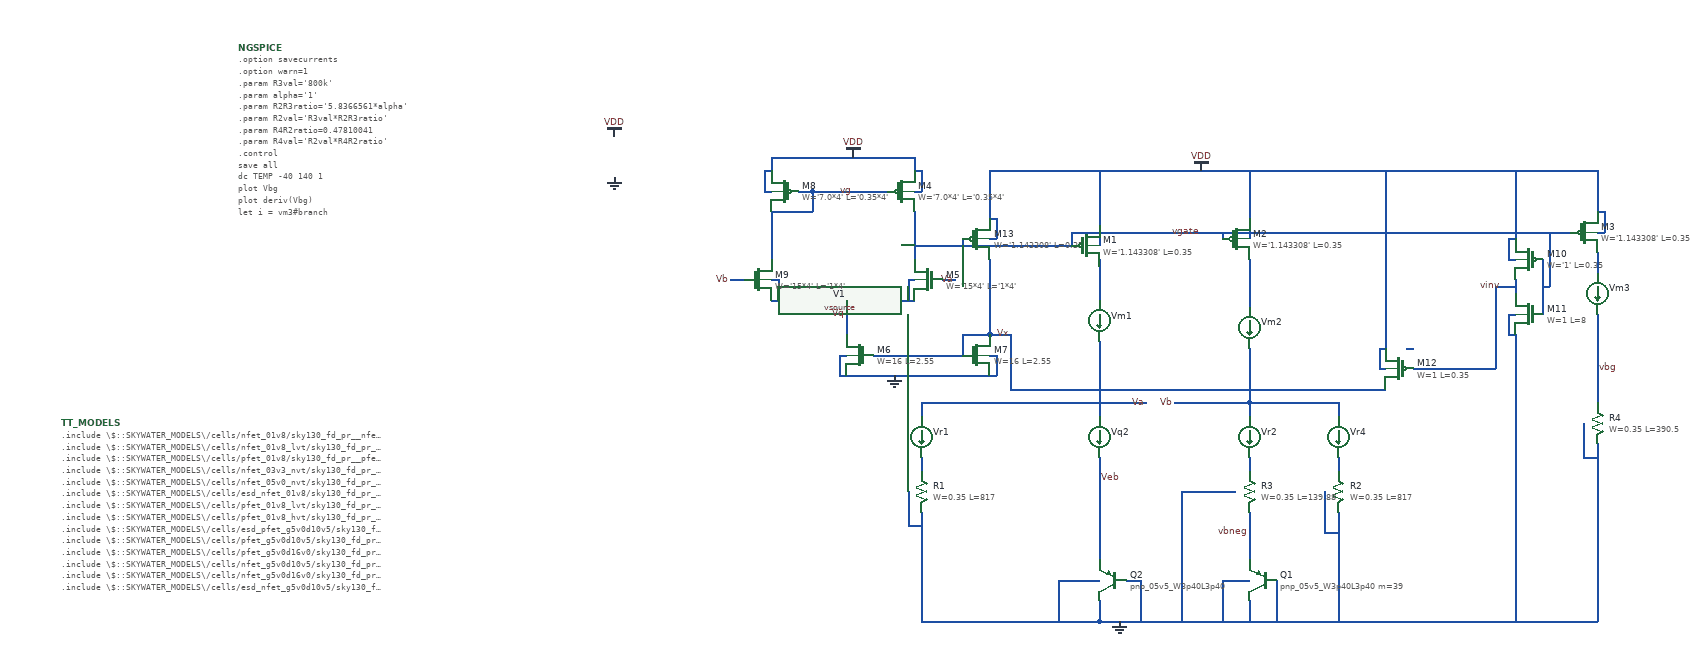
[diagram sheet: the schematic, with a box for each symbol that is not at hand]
v {xschem version=2.9.9 file_version=1.2 }
G {}
K {}
V {}
S {}
E {}
N 510 -220 760 -220 { lab=Va}
N 890 -220 990 -220 { lab=Vb}
N 990 -220 1120 -220 { lab=Vb}
N 770 70 770 100 { lab=GND}
N 770 100 870 100 { lab=GND}
N 580 100 770 100 { lab=GND}
N 710 40 770 40 { lab=GND}
N 710 40 710 100 { lab=GND}
N 830 -220 840 -220 { lab=Va}
N 700 -560 920 -560 { lab=VDD}
N 920 -560 1180 -560 { lab=VDD}
N 990 -220 990 -200 { lab=Vb}
N 990 -300 990 -220 { lab=Vb}
N 1500 -350 1500 -320 { lab=vbg}
N 1500 -320 1500 -220 { lab=vbg}
N 990 -140 990 -120 { lab=#net1}
N 1120 -220 1120 -200 { lab=Vb}
N 1120 -140 1120 -120 { lab=#net2}
N 510 -220 510 -200 { lab=Va}
N 510 -140 510 -120 { lab=#net3}
N 990 -430 990 -360 { lab=#net4}
N 990 -60 990 -40 { lab=vbneg}
N 990 -40 990 0 { lab=vbneg}
N 990 0 990 10 { lab=vbneg}
N 870 100 990 100 { lab=GND}
N 510 -60 510 100 { lab=GND}
N 1120 -60 1120 100 { lab=GND}
N 1500 -160 1500 100 { lab=GND}
N 920 100 1180 100 { lab=GND}
N 1030 40 1030 100 { lab=GND}
N 770 -220 770 -200 { lab=Va}
N 990 70 990 100 { lab=GND}
N 950 40 990 40 { lab=GND}
N 950 40 950 100 { lab=GND}
N 810 40 830 40 { lab=GND}
N 830 40 830 100 { lab=GND}
N 490 -90 490 -40 { lab=GND}
N 490 -40 510 -40 { lab=GND}
N 1100 -90 1100 -30 { lab=GND}
N 1100 -30 1120 -30 { lab=GND}
N 890 -90 970 -90 { lab=GND}
N 890 -90 890 100 { lab=GND}
N 1480 -190 1480 -140 { lab=GND}
N 1480 -140 1500 -140 { lab=GND}
N 770 -140 770 10 { lab=Veb}
N 990 -500 990 -490 { lab=VDD}
N 1500 -420 1500 -410 { lab=#net5}
N 770 -310 770 -210 { lab=Va}
N 880 -220 890 -220 { lab=Vb}
N 770 -430 770 -370 { lab=#net6}
N 990 -490 990 -460 { lab=VDD}
N 730 -470 730 -460 { lab=vgate}
N 770 -490 770 -460 { lab=VDD}
N 290 -500 350 -500 { lab=vg}
N 350 -530 350 -500 { lab=vg}
N 330 -530 350 -530 { lab=vg}
N 350 -530 460 -530 { lab=vg}
N 290 -580 290 -560 { lab=VDD}
N 290 -580 500 -580 { lab=VDD}
N 500 -580 500 -560 { lab=VDD}
N 290 -500 290 -430 { lab=vg}
N 500 -500 500 -430 { lab=vgate}
N 540 -400 560 -400 { lab=Va}
N 230 -400 250 -400 { lab=Vb}
N 290 -370 500 -370 { lab=Vq}
N 500 -530 510 -530 { lab=VDD}
N 510 -560 510 -530 { lab=VDD}
N 500 -560 510 -560 { lab=VDD}
N 280 -530 290 -530 { lab=VDD}
N 280 -560 280 -530 { lab=VDD}
N 280 -560 290 -560 { lab=VDD}
N 290 -400 300 -400 { lab=Vq}
N 300 -400 300 -370 { lab=Vq}
N 490 -400 500 -400 { lab=Vq}
N 490 -400 490 -370 { lab=Vq}
N 390 -290 400 -290 { lab=GND}
N 390 -290 390 -260 { lab=GND}
N 390 -260 400 -260 { lab=GND}
N 400 -370 400 -320 { lab=Vq}
N 440 -290 570 -290 { lab=Vx}
N 610 -290 620 -290 { lab=GND}
N 610 -430 610 -320 { lab=Vx}
N 610 -560 660 -560 { lab=VDD}
N 470 -260 610 -260 { lab=GND}
N 400 -260 470 -260 { lab=GND}
N 570 -320 570 -290 { lab=Vx}
N 570 -320 610 -320 { lab=Vx}
N 610 -560 610 -490 { lab=VDD}
N 660 -560 700 -560 { lab=VDD}
N 730 -460 730 -450 { lab=vgate}
N 500 -450 660 -450 { lab=vgate}
N 620 -290 620 -260 { lab=GND}
N 610 -260 620 -260 { lab=GND}
N 570 -460 570 -450 { lab=vgate}
N 610 -460 620 -460 { lab=VDD}
N 620 -490 620 -460 { lab=VDD}
N 610 -490 620 -490 { lab=VDD}
N 1380 -560 1380 -460 { lab=VDD}
N 1420 -430 1420 -350 { lab=vgate}
N 1370 -430 1380 -430 { lab=VDD}
N 1370 -460 1370 -430 { lab=VDD}
N 1370 -460 1380 -460 { lab=VDD}
N 1380 -400 1380 -380 { lab=vinv}
N 1370 -350 1380 -350 { lab=GND}
N 1370 -350 1370 -320 { lab=GND}
N 1370 -320 1380 -320 { lab=GND}
N 1380 -320 1380 100 { lab=GND}
N 1420 -390 1430 -390 { lab=vgate}
N 1430 -470 1430 -390 { lab=vgate}
N 1190 -560 1190 -300 { lab=VDD}
N 1180 -270 1190 -270 { lab=VDD}
N 1180 -300 1180 -270 { lab=VDD}
N 1220 -300 1230 -300 { lab=#net7}
N 1350 -390 1350 -270 { lab=vinv}
N 1350 -390 1380 -390 { lab=vinv}
N 1180 -560 1470 -560 { lab=VDD}
N 1180 100 1470 100 { lab=GND}
N 640 -240 1190 -240 { lab=Vx}
N 640 -320 640 -240 { lab=Vx}
N 610 -320 640 -320 { lab=Vx}
N 1170 -470 1460 -470 { lab=vgate}
N 760 -220 830 -220 { lab=Va}
N 510 100 580 100 { lab=GND}
N 770 -560 770 -490 { lab=VDD}
N 990 -560 990 -500 { lab=VDD}
N 660 -450 730 -450 { lab=vgate}
N 730 -470 920 -470 { lab=vgate}
N 920 -470 1170 -470 { lab=vgate}
N 950 -470 950 -460 { lab=vgate}
N 1180 -300 1190 -300 { lab=VDD}
N 1470 -560 1500 -560 { lab=VDD}
N 1230 -270 1350 -270 { lab=vinv}
N 1470 100 1500 100 { lab=GND}
N 1500 -440 1500 -420 { lab=#net5}
N 1500 -470 1510 -470 { lab=VDD}
N 1510 -500 1510 -470 { lab=VDD}
N 1500 -500 1510 -500 { lab=VDD}
N 1500 -560 1500 -500 { lab=VDD}
N 770 -460 770 -450 { lab=VDD}
C {devices/code.sym} -750 -190 0 0 {name=TT_MODELS
only_toplevel=true
format="tcleval( @value )"
value="
.include \\\\$::SKYWATER_MODELS\\\\/cells/nfet_01v8/sky130_fd_pr__nfet_01v8__tt.corner.spice
.include \\\\$::SKYWATER_MODELS\\\\/cells/nfet_01v8_lvt/sky130_fd_pr__nfet_01v8_lvt__tt.corner.spice
.include \\\\$::SKYWATER_MODELS\\\\/cells/pfet_01v8/sky130_fd_pr__pfet_01v8__tt.corner.spice
.include \\\\$::SKYWATER_MODELS\\\\/cells/nfet_03v3_nvt/sky130_fd_pr__nfet_03v3_nvt__tt.corner.spice
.include \\\\$::SKYWATER_MODELS\\\\/cells/nfet_05v0_nvt/sky130_fd_pr__nfet_05v0_nvt__tt.corner.spice
.include \\\\$::SKYWATER_MODELS\\\\/cells/esd_nfet_01v8/sky130_fd_pr__esd_nfet_01v8__tt.corner.spice
.include \\\\$::SKYWATER_MODELS\\\\/cells/pfet_01v8_lvt/sky130_fd_pr__pfet_01v8_lvt__tt.corner.spice
.include \\\\$::SKYWATER_MODELS\\\\/cells/pfet_01v8_hvt/sky130_fd_pr__pfet_01v8_hvt__tt.corner.spice
.include \\\\$::SKYWATER_MODELS\\\\/cells/esd_pfet_g5v0d10v5/sky130_fd_pr__esd_pfet_g5v0d10v5__tt.corner.spice
.include \\\\$::SKYWATER_MODELS\\\\/cells/pfet_g5v0d10v5/sky130_fd_pr__pfet_g5v0d10v5__tt.corner.spice
.include \\\\$::SKYWATER_MODELS\\\\/cells/pfet_g5v0d16v0/sky130_fd_pr__pfet_g5v0d16v0__tt.corner.spice
.include \\\\$::SKYWATER_MODELS\\\\/cells/nfet_g5v0d10v5/sky130_fd_pr__nfet_g5v0d10v5__tt.corner.spice
.include \\\\$::SKYWATER_MODELS\\\\/cells/nfet_g5v0d16v0/sky130_fd_pr__nfet_g5v0d16v0__tt_discrete.corner.spice
.include \\\\$::SKYWATER_MODELS\\\\/cells/esd_nfet_g5v0d10v5/sky130_fd_pr__esd_nfet_g5v0d10v5__tt.corner.spice
.include \\\\$::SKYWATER_MODELS\\\\/models/corners/tt/nonfet.spice
* Mismatch parameters
.include \\\\$::SKYWATER_MODELS\\\\/cells/nfet_01v8/sky130_fd_pr__nfet_01v8__mismatch.corner.spice
.include \\\\$::SKYWATER_MODELS\\\\/cells/pfet_01v8/sky130_fd_pr__pfet_01v8__mismatch.corner.spice
.include \\\\$::SKYWATER_MODELS\\\\/cells/nfet_01v8_lvt/sky130_fd_pr__nfet_01v8_lvt__mismatch.corner.spice
.include \\\\$::SKYWATER_MODELS\\\\/cells/pfet_01v8_lvt/sky130_fd_pr__pfet_01v8_lvt__mismatch.corner.spice
.include \\\\$::SKYWATER_MODELS\\\\/cells/pfet_01v8_hvt/sky130_fd_pr__pfet_01v8_hvt__mismatch.corner.spice
.include \\\\$::SKYWATER_MODELS\\\\/cells/nfet_g5v0d10v5/sky130_fd_pr__nfet_g5v0d10v5__mismatch.corner.spice
.include \\\\$::SKYWATER_MODELS\\\\/cells/pfet_g5v0d10v5/sky130_fd_pr__pfet_g5v0d10v5__mismatch.corner.spice
.include \\\\$::SKYWATER_MODELS\\\\/cells/nfet_05v0_nvt/sky130_fd_pr__nfet_05v0_nvt__mismatch.corner.spice
.include \\\\$::SKYWATER_MODELS\\\\/cells/nfet_03v3_nvt/sky130_fd_pr__nfet_03v3_nvt__mismatch.corner.spice
* Resistor\\\\$::SKYWATER_MODELS\\\\/Capacitor
.include \\\\$::SKYWATER_MODELS\\\\/models/r+c/res_typical__cap_typical.spice
.include \\\\$::SKYWATER_MODELS\\\\/models/r+c/res_typical__cap_typical__lin.spice
* Special cells
.include \\\\$::SKYWATER_MODELS\\\\/models/corners/tt/specialized_cells.spice
* All models
.include \\\\$::SKYWATER_MODELS\\\\/models/all.spice
.include \\\\$::SKYWATER_MODELS\\\\/cells/pnp_05v5/sky130_fd_pr__pnp_05v5_W3p40L3p40.model.spice
* Corner
.include \\\\$::SKYWATER_MODELS\\\\/models/corners/tt/rf.spice
"}
C {devices/vsource.sym} 60 -580 0 0 {name=V1 net_name=true value=1.8}
C {devices/vdd.sym} 60 -610 0 0 {name=l8 lab=VDD}
C {devices/gnd.sym} 60 -550 0 0 {name=l9 lab=GND}
C {devices/code_shown.sym} -490 -740 0 0 {name=NGSPICE
only_toplevel=true
spice_ignore=false
value="
.option savecurrents
.option warn=1
.param R3val='800k'
.param alpha='1'
.param R2R3ratio='5.8366561*alpha'
.param R2val='R3val*R2R3ratio' 
.param R4R2ratio=0.47810041
.param R4val='R2val*R4R2ratio'
.control
save all
dc TEMP -40 140 1
plot Vbg
plot deriv(Vbg)
let i = vm3#branch
let indx = 67
*indx is the index of temperature sweep for 27degC
echo 'Vbg @ 27degC'
let vbg27c = vbg[indx]
print vbg27c
echo 'dVbe/degC & ppm @ 27degC'
print deriv(vbg)[indx] deriv(vbg)[indx]/vbg27c
echo 'ppm real'
print (vbg[110]-vbg[40])/vbg[67]/(70-0)*1e6
plot deriv(vbg)/vbg27c
plot v(va, vb) vs i
plot vm1#branch vm2#branch vm3#branch
let vsg = vdd - vgate
let vsd1 = vdd - va
let vsd2 = vdd - vb
let vsd3 = vdd - vbg
let vthp = @m.xm1.msky130_fd_pr__pfet_01v8_lvt['vth']
let vov = vsg - vthp
plot vov vsd1 vsd2 vsd3
let deltav = vb - vbneg
let r4 =vbg/vm3#branch
let r1 =va/vr1#branch
let r2 =vb/vr4#branch
let r3 =deltav/vr2#branch
let vptat =(r2/r3*deltav)
let sum = veb+vptat
plot veb vptat sum
plot deriv(veb) deriv(vptat)
let TCratio=deriv(veb)/deriv(vptat)
plot TCratio
plot vb - va
echo 'alpha correction factor'
let alpha=TCratio[indx]
print alpha
let gm1=@m.xm1.msky130_fd_pr__pfet_01v8_lvt[gm]
let gm2=@m.xm2.msky130_fd_pr__pfet_01v8_lvt[gm]
let Av2=gm2 * ((r3 + r3/ln(39)) * r2 / (r3 + r3/ln(39) + r2) )
let Av1=gm1 * (r1 * r3/ln(39))/(r1 + r3/ln(39))
plot Av1 Av2 Av2/Av1
*write tsmc_bandgap_temp.raw
*op
*write tsmc_bandgap_op.raw
*print vbg 
*print (vb - vbneg)
.endc
" }
C {sky130_fd_pr/pnp_05v5.sym} 790 40 0 1 {name=Q2
model=pnp_05v5_W3p40L3p40
spiceprefix=X
}
C {devices/gnd.sym} 800 100 0 0 {name=l1 lab=GND}
C {devices/lab_pin.sym} 840 -220 3 0 {name=l5 lab=Va}
C {devices/lab_pin.sym} 880 -220 3 0 {name=l6 lab=Vb}
C {devices/vdd.sym} 920 -560 0 0 {name=l7 lab=VDD}
C {devices/ammeter.sym} 1120 -170 0 0 {name=Vr4}
C {devices/ammeter.sym} 990 -170 0 0 {name=Vr2}
C {devices/ammeter.sym} 770 -340 0 0 {name=Vm1}
C {devices/ammeter.sym} 990 -330 0 0 {name=Vm2}
C {devices/ammeter.sym} 1500 -380 0 0 {name=Vm3}
C {devices/ammeter.sym} 510 -170 0 0 {name=Vr1}
C {devices/ammeter.sym} 770 -170 0 0 {name=Vq2}
C {sky130_fd_pr/pnp_05v5.sym} 1010 40 0 1 {name=Q1
model="pnp_05v5_W3p40L3p40 m=39"
spiceprefix=X
}
C {devices/lab_pin.sym} 990 -30 0 0 {name=l4 lab=vbneg}
C {devices/lab_pin.sym} 770 -110 2 0 {name=l10 lab=Veb}
C {devices/lab_wire.sym} 920 -470 0 0 {name=l11 lab=vgate}
C {devices/vdd.sym} 410 -580 0 0 {name=l14 lab=VDD}
C {devices/lab_pin.sym} 230 -400 3 0 {name=l15 lab=Vb}
C {devices/lab_pin.sym} 560 -400 3 0 {name=l16 lab=Va}
C {devices/gnd.sym} 470 -260 0 0 {name=l17 lab=GND}
C {sky130_fd_pr/pfet_01v8_lvt.sym} 480 -530 0 0 {name=M4
L='0.35*4'
W='7.0*4'
nf=1
mult=1
ad="'int((nf+1)/2) * W/nf * 0.29'" 
pd="'2*int((nf+1)/2) * (W/nf + 0.29)'"
as="'int((nf+2)/2) * W/nf * 0.29'" 
ps="'2*int((nf+2)/2) * (W/nf + 0.29)'"
nrd="'0.29 / W'" nrs="'0.29 / W'"
sa=0 sb=0 sd=0
model=pfet_01v8_lvt
spiceprefix=X
}
C {sky130_fd_pr/nfet_01v8_lvt.sym} 520 -400 0 1 {name=M5
L='1*4'
W='15*4'
nf=1
mult=4
ad="'int((nf+1)/2) * W/nf * 0.29'" 
pd="'2*int((nf+1)/2) * (W/nf + 0.29)'"
as="'int((nf+2)/2) * W/nf * 0.29'" 
ps="'2*int((nf+2)/2) * (W/nf + 0.29)'"
nrd="'0.29 / W'" nrs="'0.29 / W'"
sa=0 sb=0 sd=0
model=nfet_01v8_lvt
spiceprefix=X
}
C {sky130_fd_pr/nfet_01v8_lvt.sym} 420 -290 0 1 {name=M6
L=2.55
W=16
nf=1
mult=16
ad="'int((nf+1)/2) * W/nf * 0.29'" 
pd="'2*int((nf+1)/2) * (W/nf + 0.29)'"
as="'int((nf+2)/2) * W/nf * 0.29'" 
ps="'2*int((nf+2)/2) * (W/nf + 0.29)'"
nrd="'0.29 / W'" nrs="'0.29 / W'"
sa=0 sb=0 sd=0
model=nfet_01v8_lvt
spiceprefix=X
}
C {sky130_fd_pr/pfet_01v8_lvt.sym} 310 -530 0 1 {name=M8
L='0.35*4'
W='7.0*4'
nf=1
mult=1
ad="'int((nf+1)/2) * W/nf * 0.29'" 
pd="'2*int((nf+1)/2) * (W/nf + 0.29)'"
as="'int((nf+2)/2) * W/nf * 0.29'" 
ps="'2*int((nf+2)/2) * (W/nf + 0.29)'"
nrd="'0.29 / W'" nrs="'0.29 / W'"
sa=0 sb=0 sd=0
model=pfet_01v8_lvt
spiceprefix=X
}
C {sky130_fd_pr/nfet_01v8_lvt.sym} 270 -400 0 0 {name=M9
L='1*4'
W='15*4'
nf=1
mult=4
ad="'int((nf+1)/2) * W/nf * 0.29'" 
pd="'2*int((nf+1)/2) * (W/nf + 0.29)'"
as="'int((nf+2)/2) * W/nf * 0.29'" 
ps="'2*int((nf+2)/2) * (W/nf + 0.29)'"
nrd="'0.29 / W'" nrs="'0.29 / W'"
sa=0 sb=0 sd=0
model=nfet_01v8_lvt
spiceprefix=X
}
C {sky130_fd_pr/pfet_01v8_lvt.sym} 1400 -430 0 1 {name=M10
L=0.35
W='1'
nf=1
mult=50
ad="'int((nf+1)/2) * W/nf * 0.29'" 
pd="'2*int((nf+1)/2) * (W/nf + 0.29)'"
as="'int((nf+2)/2) * W/nf * 0.29'" 
ps="'2*int((nf+2)/2) * (W/nf + 0.29)'"
nrd="'0.29 / W'" nrs="'0.29 / W'"
sa=0 sb=0 sd=0
model=pfet_01v8_lvt
spiceprefix=X
}
C {sky130_fd_pr/nfet_01v8_lvt.sym} 1400 -350 0 1 {name=M11
L=8
W=1
nf=1
mult=1
ad="'int((nf+1)/2) * W/nf * 0.29'" 
pd="'2*int((nf+1)/2) * (W/nf + 0.29)'"
as="'int((nf+2)/2) * W/nf * 0.29'" 
ps="'2*int((nf+2)/2) * (W/nf + 0.29)'"
nrd="'0.29 / W'" nrs="'0.29 / W'"
sa=0 sb=0 sd=0
model=nfet_01v8_lvt
spiceprefix=X
}
C {sky130_fd_pr/pfet_01v8_lvt.sym} 1210 -270 0 1 {name=M12
L=0.35
W=1
nf=1
mult=1
ad="'int((nf+1)/2) * W/nf * 0.29'" 
pd="'2*int((nf+1)/2) * (W/nf + 0.29)'"
as="'int((nf+2)/2) * W/nf * 0.29'" 
ps="'2*int((nf+2)/2) * (W/nf + 0.29)'"
nrd="'0.29 / W'" nrs="'0.29 / W'"
sa=0 sb=0 sd=0
model=pfet_01v8_lvt
spiceprefix=X
}
C {devices/lab_pin.sym} 410 -530 1 0 {name=l2 lab=vg}
C {devices/lab_pin.sym} 640 -320 1 0 {name=l12 lab=Vx}
C {devices/lab_pin.sym} 1360 -390 0 0 {name=l13 lab=vinv}
C {devices/lab_pin.sym} 400 -350 0 0 {name=l18 lab=Vq}
C {sky130_fd_pr/nfet_01v8_lvt.sym} 590 -290 0 0 {name=M7
L=2.55
W=16
nf=1
mult=16
ad="'int((nf+1)/2) * W/nf * 0.29'" 
pd="'2*int((nf+1)/2) * (W/nf + 0.29)'"
as="'int((nf+2)/2) * W/nf * 0.29'" 
ps="'2*int((nf+2)/2) * (W/nf + 0.29)'"
nrd="'0.29 / W'" nrs="'0.29 / W'"
sa=0 sb=0 sd=0
model=nfet_01v8_lvt
spiceprefix=X
}
C {sky130_fd_pr/pfet_01v8_lvt.sym} 590 -460 0 0 {name=M13
L=0.35
W='1.143308'
nf=1
mult=1
ad="'int((nf+1)/2) * W/nf * 0.29'" 
pd="'2*int((nf+1)/2) * (W/nf + 0.29)'"
as="'int((nf+2)/2) * W/nf * 0.29'" 
ps="'2*int((nf+2)/2) * (W/nf + 0.29)'"
nrd="'0.29 / W'" nrs="'0.29 / W'"
sa=0 sb=0 sd=0
model=pfet_01v8_lvt
spiceprefix=X
}
C {sky130_fd_pr/pfet_01v8_lvt.sym} 750 -450 0 0 {name=M1
L=0.35
W='1.143308'
nf=1
mult=1
ad="'int((nf+1)/2) * W/nf * 0.29'" 
pd="'2*int((nf+1)/2) * (W/nf + 0.29)'"
as="'int((nf+2)/2) * W/nf * 0.29'" 
ps="'2*int((nf+2)/2) * (W/nf + 0.29)'"
nrd="'0.29 / W'" nrs="'0.29 / W'"
sa=0 sb=0 sd=0
model=pfet_01v8_lvt
spiceprefix=X
}
C {sky130_fd_pr/pfet_01v8_lvt.sym} 970 -460 0 0 {name=M2
L=0.35
W='1.143308'
nf=1
mult=1
ad="'int((nf+1)/2) * W/nf * 0.29'" 
pd="'2*int((nf+1)/2) * (W/nf + 0.29)'"
as="'int((nf+2)/2) * W/nf * 0.29'" 
ps="'2*int((nf+2)/2) * (W/nf + 0.29)'"
nrd="'0.29 / W'" nrs="'0.29 / W'"
sa=0 sb=0 sd=0
model=pfet_01v8_lvt
spiceprefix=X
}
C {sky130_fd_pr/pfet_01v8_lvt.sym} 1480 -470 0 0 {name=M3
L=0.35
W='1.143308'
nf=1
mult=1
ad="'int((nf+1)/2) * W/nf * 0.29'" 
pd="'2*int((nf+1)/2) * (W/nf + 0.29)'"
as="'int((nf+2)/2) * W/nf * 0.29'" 
ps="'2*int((nf+2)/2) * (W/nf + 0.29)'"
nrd="'0.29 / W'" nrs="'0.29 / W'"
sa=0 sb=0 sd=0
model=pfet_01v8_lvt
spiceprefix=X
}
C {sky130_fd_pr/res_xhigh_po_0p35.sym} 510 -90 0 0 {name=R1
W=0.35
L=817
model=res_xhigh_po_0p35
spiceprefix=X
mult=1}
C {sky130_fd_pr/res_xhigh_po_0p35.sym} 1120 -90 0 0 {name=R2
W=0.35
L=817
model=res_xhigh_po_0p35
spiceprefix=X
mult=1}
C {sky130_fd_pr/res_xhigh_po_0p35.sym} 990 -90 0 0 {name=R3
W=0.35
L=139.88
model=res_xhigh_po_0p35
spiceprefix=X
mult=1}
C {sky130_fd_pr/res_xhigh_po_0p35.sym} 1500 -190 0 0 {name=R4
W=0.35
L=390.5
model=res_xhigh_po_0p35
spiceprefix=X
mult=1}
C {devices/lab_pin.sym} 1500 -270 0 1 {name=l3 lab=vbg}
